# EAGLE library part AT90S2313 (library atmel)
MICROCONTROLLER 2 Kbytes FLASH 128 bytes SRAM 128 bytes EEPROM UART

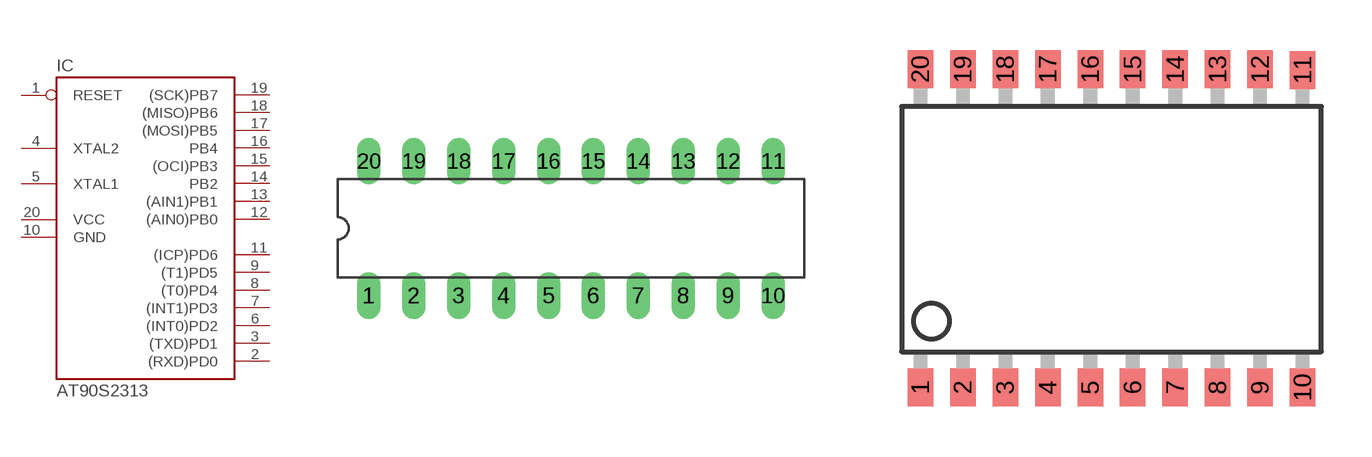
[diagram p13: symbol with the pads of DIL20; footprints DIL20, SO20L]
Designator prefix IC

## AT90S2313P (OC_FARNELL: unknown; OC_NEWARK: unknown)  [DIL20]
1  RESET
2  (RXD)PD0
3  (TXD)PD1
4  XTAL2
5  XTAL1
6  (INT0)PD2
7  (INT1)PD3
8  (T0)PD4
9  (T1)PD5
10  GND  pwr
11  (ICP)PD6
12  (AIN0)PB0
13  (AIN1)PB1
14  PB2
15  (OCI)PB3
16  PB4
17  (MOSI)PB5
18  (MISO)PB6
19  (SCK)PB7
20  VCC  pwr

## AT90S2313S (OC_FARNELL: unknown; OC_NEWARK: unknown)  [SO20L]
Pads as for DIL20

## AT90S2313V  [MLF20-4X4]
1  (TXD)PD1
2  XTAL2
3  XTAL1
4  (INT0)PD2
5  (INT1)PD3
6  (T0)PD4
7  (T1)PD5
8  GND  pwr
9  (ICP)PD6
10  (AIN0)PB0
11  (AIN1)PB1
12  PB2
13  (OCI)PB3
14  PB4
15  (MOSI)PB5
16  (MISO)PB6
17  (SCK)PB7
18  VCC  pwr
19  RESET
20  (RXD)PD0
TH  GND  pwr

## Footprint DIL20 (pad centres in mm)
Dual In Line
drill 0.813 long: 1 -11.43,-3.81; 2 -8.89,-3.81; 3 -6.35,-3.81; 4 -3.81,-3.81; 5 -1.27,-3.81; 6 1.27,-3.81; 7 3.81,-3.81; 8 6.35,-3.81; 9 8.89,-3.81; 10 11.43,-3.81; 11 11.43,3.81; 12 8.89,3.81; 13 6.35,3.81; 14 3.81,3.81; 15 1.27,3.81; 16 -1.27,3.81; 17 -3.81,3.81; 18 -6.35,3.81; 19 -8.89,3.81; 20 -11.43,3.81

## Footprint SO20L (pad centres in mm)
Small Outline Package SOIC 0.300"
smd 0.762 x 1.143: 1 -5.08,-5.131; 2 -3.81,-5.131; 3 -2.54,-5.131; 4 -1.27,-5.131; 5 0,-5.131; 6 1.27,-5.131; 7 2.54,-5.131; 8 3.81,-5.131; 9 5.08,-5.131; 10 6.35,-5.131; 11 6.35,4.369; 12 5.08,4.394; 13 3.81,4.394; 14 2.54,4.394; 15 1.27,4.394; 16 0,4.394; 17 -1.27,4.394; 18 -2.54,4.394; 19 -3.81,4.394; 20 -5.08,4.394

## Footprint MLF20-4X4 (pad centres in mm)
20M1 20-pad, 4 x 4 x 0.8 mm Body Lead Pitch 0.50 mm, 2.6 mm Exposed Pad, Micro Lead Frame Package (MLF) Source: Data sheet
smd 0.8 x 0.3: 1 -1.85,1; 2 -1.85,0.5; 3 -1.85,0; 4 -1.85,-0.5; 5 -1.85,-1; 11 1.85,-1; 12 1.85,-0.5; 13 1.85,0; 14 1.85,0.5; 15 1.85,1
smd 0.3 x 0.8: 6 -1,-1.85; 7 -0.5,-1.85; 8 0,-1.85; 9 0.5,-1.85; 10 1,-1.85; 16 1,1.85; 17 0.5,1.85; 18 0,1.85; 19 -0.5,1.85; 20 -1,1.85
smd 2.6 x 2.6: TH 0,0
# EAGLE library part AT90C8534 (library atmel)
MICROCONTROLLER 8 Kbytes FLASH 512 bytes EEPROM 256 bytes SRAM 6-channel 10-bit A/D

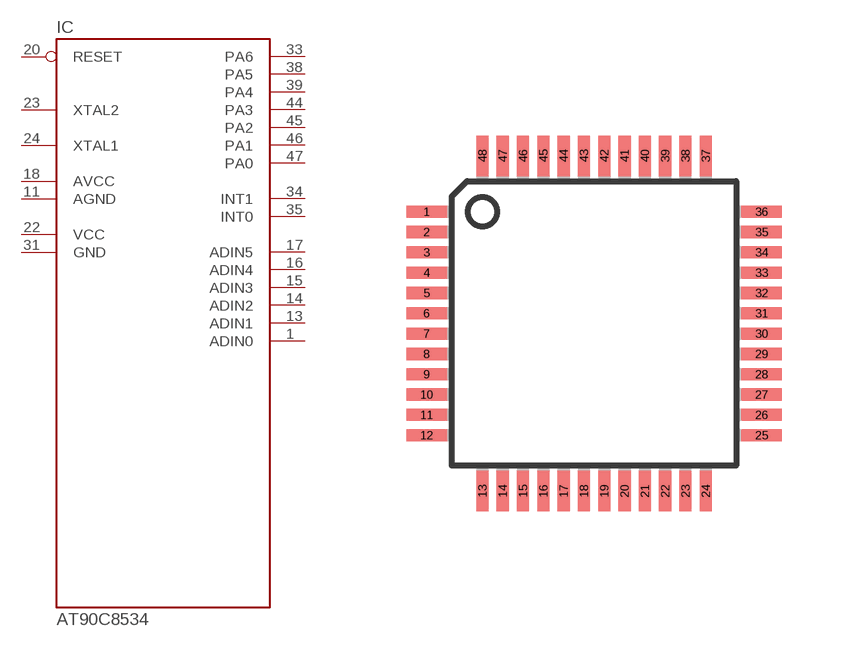
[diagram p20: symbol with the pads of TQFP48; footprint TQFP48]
Designator prefix IC

## AT90C8534A (OC_FARNELL: unknown; OC_NEWARK: unknown)  [TQFP48]
1  ADIN0  in
2  NC1  nc
3  NC2  nc
4  NC3  nc
5  NC4  nc
6  NC5  nc
7  NC6  nc
8  NC7  nc
9  NC8  nc
10  NC9  nc
11  AGND  in
12  NC10  nc
13  ADIN1  in
14  ADIN2  in
15  ADIN3  in
16  ADIN4  in
17  ADIN5  in
18  AVCC  in
19  NC11  nc
20  RESET  in
21  NC12  nc
22  VCC  pwr
23  XTAL2
24  XTAL1
25  NC13  nc
26  NC14  nc
27  NC15  nc
28  NC16  nc
29  NC17  nc
30  NC18  nc
31  GND  pwr
32  NC19  nc
33  PA6
34  INT1  in
35  INT0  in
36  NC20  nc
37  NC21  nc
38  PA5
39  PA4
40  NC22  nc
41  NC23  nc
42  NC24  nc
43  NC25  nc
44  PA3
45  PA2
46  PA1
47  PA0
48  NC26  nc

## Footprint TQFP48 (pad centres in mm)
Thin Plasic Quad Flat Package
smd 1.016 x 0.305: 1 -4.191,2.794; 2 -4.191,2.286; 3 -4.191,1.778; 4 -4.191,1.27; 5 -4.191,0.762; 6 -4.191,0.254; 7 -4.191,-0.254; 8 -4.191,-0.762; 9 -4.191,-1.27; 10 -4.191,-1.778; 11 -4.191,-2.286; 12 -4.191,-2.794; 25 4.191,-2.794; 26 4.191,-2.286; 27 4.191,-1.778; 28 4.191,-1.27; 29 4.191,-0.762; 30 4.191,-0.254; 31 4.191,0.254; 32 4.191,0.762; 33 4.191,1.27; 34 4.191,1.778; 35 4.191,2.286; 36 4.191,2.794
smd 0.305 x 1.016: 13 -2.794,-4.191; 14 -2.286,-4.191; 15 -1.778,-4.191; 16 -1.27,-4.191; 17 -0.762,-4.191; 18 -0.254,-4.191; 19 0.254,-4.191; 20 0.762,-4.191; 21 1.27,-4.191; 22 1.778,-4.191; 23 2.286,-4.191; 24 2.794,-4.191; 37 2.794,4.191; 38 2.286,4.191; 39 1.778,4.191; 40 1.27,4.191; 41 0.762,4.191; 42 0.254,4.191; 43 -0.254,4.191; 44 -0.762,4.191; 45 -1.27,4.191; 46 -1.778,4.191; 47 -2.286,4.191; 48 -2.794,4.191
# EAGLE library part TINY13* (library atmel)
8-bit AVR Microcontroller with 1K Bytes In-System Programmable Flash Source: http://www.atmel.com/dyn/resources/prod_documents/2535S.pdf

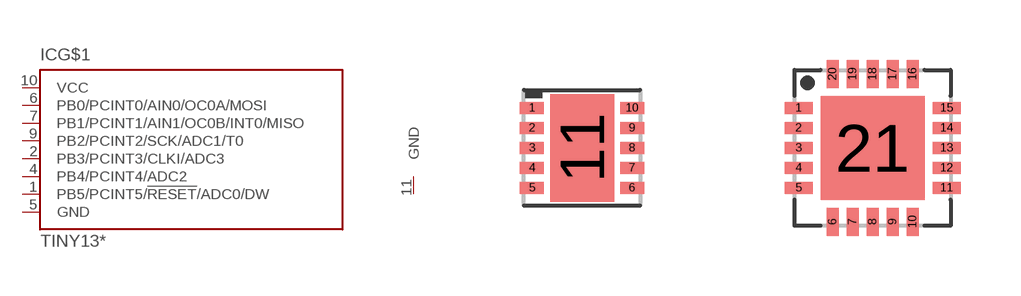
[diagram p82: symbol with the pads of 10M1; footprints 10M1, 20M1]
Designator prefix IC; gates G$1=TINY13 P=GND

## TINY13-20MM0 (MPN: ATTINY13A-MMU; OC_FARNELL: 1715516; OC_NEWARK: 15R0298), TINY13V-10MM0 (MPN: ATTINY13A-MMU; OC_FARNELL: 1715516; OC_NEWARK: 15R0298)  [10M1]
1  G$1:PB5/PCINT5/!RESET!/ADC0/DW
2  G$1:PB3/PCINT3/CLKI/ADC3
4  G$1:PB4/PCINT4/ADC2
5  G$1:GND  pwr
6  G$1:PB0/PCINT0/AIN0/OC0A/MOSI
7  G$1:PB1/PCINT1/AIN1/OC0B/INT0/MISO
9  G$1:PB2/PCINT2/SCK/ADC1/T0
10  G$1:VCC  pwr
11  P:GND  pwr

## TINY13-20MU (MPN: ATTINY13A-MU; OC_FARNELL: 1715517; OC_NEWARK: 15R0299), TINY13V-10MU (MPN: ATTINY13V-10MU; OC_FARNELL: 1455134; OC_NEWARK: 58M3772)  [20M1]
1  G$1:PB5/PCINT5/!RESET!/ADC0/DW
2  G$1:PB3/PCINT3/CLKI/ADC3
5  G$1:PB4/PCINT4/ADC2
8  P:GND  pwr
11  G$1:PB0/PCINT0/AIN0/OC0A/MOSI
12  G$1:PB1/PCINT1/AIN1/OC0B/INT0/MISO
14  G$1:PB2/PCINT2/SCK/ADC1/T0
15  G$1:VCC  pwr
21  G$1:GND  pwr

## Footprint 10M1 (pad centres in mm)
10M1 10-pad, 3 x 3 x 1.0 mm Body Lead Pitch 0.50 mm, 1.64 x 2.60 mm Exposed Pad, Micro Lead Frame Package MLF10, QFN10 Source: http://www.atmel.com/dyn/resources/prod_documents/2535S.pdf
smd 0.6 x 0.3: 1 -1.25,1; 2 -1.25,0.5; 3 -1.25,0; 4 -1.25,-0.5; 5 -1.25,-1; 6 1.25,-1; 7 1.25,-0.5; 8 1.25,0; 9 1.25,0.5; 10 1.25,1
smd 1.6 x 2.7: 11 0,0

## Footprint 20M1 (pad centres in mm)
20M1 20-pad, 4 x 4 x 0.8 mm Body Lead Pitch 0.50 mm, 2.6 mm Exposed Pad, Micro Lead Frame Package (MLF) Source: http://www.atmel.com/dyn/resources/prod_documents/2535S.pdf
smd 0.7 x 0.3: 1 -1.85,1; 2 -1.85,0.5; 3 -1.85,0; 4 -1.85,-0.5; 5 -1.85,-1; 11 1.85,-1; 12 1.85,-0.5; 13 1.85,0; 14 1.85,0.5; 15 1.85,1
smd 0.3 x 0.7: 6 -1,-1.85; 7 -0.5,-1.85; 8 0,-1.85; 9 0.5,-1.85; 10 1,-1.85; 16 1,1.85; 17 0.5,1.85; 18 0,1.85; 19 -0.5,1.85; 20 -1,1.85
smd 2.6 x 2.6: 21 0,0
